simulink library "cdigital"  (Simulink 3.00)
libraries: ballbeam x1

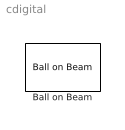
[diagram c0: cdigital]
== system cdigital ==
  Ball on Beam : ballbeam/Ball on Beam
